VERSION 5.8 ;
BUSBITCHARS "[]" ;
DIVIDERCHAR "/" ;
UNITS
    DATABASE MICRONS 1000 ;
END UNITS

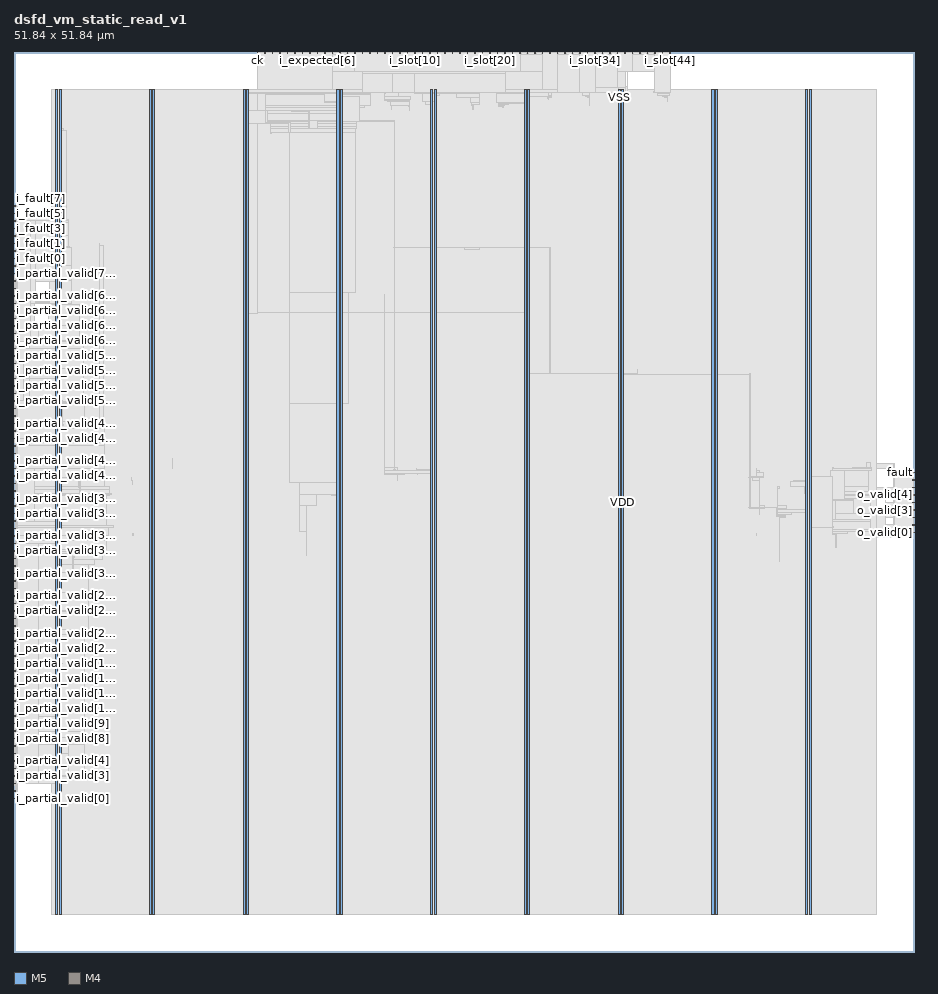
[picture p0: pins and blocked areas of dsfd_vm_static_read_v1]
MACRO dsfd_vm_static_read_v1
  FOREIGN dsfd_vm_static_read_v1 0 0 ;
  CLASS BLOCK ;
  SIZE 51.84 BY 51.84 ;
  PIN ck
    DIRECTION INPUT ;
    USE SIGNAL ;
    PORT
      LAYER M5 ;
        RECT  14.016 51.756 14.04 51.84 ;
    END
  END ck
  PIN fault
    DIRECTION OUTPUT ;
    USE SIGNAL ;
    PORT
      LAYER M4 ;
        RECT  51.756 27.6 51.84 27.624 ;
    END
  END fault
  PIN i_expected[0]
    DIRECTION INPUT ;
    USE SIGNAL ;
    PORT
      LAYER M5 ;
        RECT  14.88 51.756 14.904 51.84 ;
    END
  END i_expected[0]
  PIN i_expected[1]
    DIRECTION INPUT ;
    USE SIGNAL ;
    PORT
      LAYER M5 ;
        RECT  15.312 51.756 15.336 51.84 ;
    END
  END i_expected[1]
  PIN i_expected[2]
    DIRECTION INPUT ;
    USE SIGNAL ;
    PORT
      LAYER M5 ;
        RECT  15.744 51.756 15.768 51.84 ;
    END
  END i_expected[2]
  PIN i_expected[3]
    DIRECTION INPUT ;
    USE SIGNAL ;
    PORT
      LAYER M5 ;
        RECT  16.176 51.756 16.2 51.84 ;
    END
  END i_expected[3]
  PIN i_expected[4]
    DIRECTION INPUT ;
    USE SIGNAL ;
    PORT
      LAYER M5 ;
        RECT  16.608 51.756 16.632 51.84 ;
    END
  END i_expected[4]
  PIN i_expected[5]
    DIRECTION INPUT ;
    USE SIGNAL ;
    PORT
      LAYER M5 ;
        RECT  17.04 51.756 17.064 51.84 ;
    END
  END i_expected[5]
  PIN i_expected[6]
    DIRECTION INPUT ;
    USE SIGNAL ;
    PORT
      LAYER M5 ;
        RECT  17.472 51.756 17.496 51.84 ;
    END
  END i_expected[6]
  PIN i_expected[7]
    DIRECTION INPUT ;
    USE SIGNAL ;
    PORT
      LAYER M5 ;
        RECT  17.904 51.756 17.928 51.84 ;
    END
  END i_expected[7]
  PIN i_expected[8]
    DIRECTION INPUT ;
    USE SIGNAL ;
    PORT
      LAYER M5 ;
        RECT  18.336 51.756 18.36 51.84 ;
    END
  END i_expected[8]
  PIN i_fault[0]
    DIRECTION INPUT ;
    USE SIGNAL ;
    PORT
      LAYER M4 ;
        RECT  0 39.936 0.084 39.96 ;
    END
  END i_fault[0]
  PIN i_fault[1]
    DIRECTION INPUT ;
    USE SIGNAL ;
    PORT
      LAYER M4 ;
        RECT  0 40.368 0.084 40.392 ;
    END
  END i_fault[1]
  PIN i_fault[2]
    DIRECTION INPUT ;
    USE SIGNAL ;
    PORT
      LAYER M4 ;
        RECT  0 40.8 0.084 40.824 ;
    END
  END i_fault[2]
  PIN i_fault[3]
    DIRECTION INPUT ;
    USE SIGNAL ;
    PORT
      LAYER M4 ;
        RECT  0 41.232 0.084 41.256 ;
    END
  END i_fault[3]
  PIN i_fault[4]
    DIRECTION INPUT ;
    USE SIGNAL ;
    PORT
      LAYER M4 ;
        RECT  0 41.664 0.084 41.688 ;
    END
  END i_fault[4]
  PIN i_fault[5]
    DIRECTION INPUT ;
    USE SIGNAL ;
    PORT
      LAYER M4 ;
        RECT  0 42.096 0.084 42.12 ;
    END
  END i_fault[5]
  PIN i_fault[6]
    DIRECTION INPUT ;
    USE SIGNAL ;
    PORT
      LAYER M4 ;
        RECT  0 42.528 0.084 42.552 ;
    END
  END i_fault[6]
  PIN i_fault[7]
    DIRECTION INPUT ;
    USE SIGNAL ;
    PORT
      LAYER M4 ;
        RECT  0 42.96 0.084 42.984 ;
    END
  END i_fault[7]
  PIN i_partial_valid[0]
    DIRECTION INPUT ;
    USE SIGNAL ;
    PORT
      LAYER M4 ;
        RECT  0 8.832 0.084 8.856 ;
    END
  END i_partial_valid[0]
  PIN i_partial_valid[10]
    DIRECTION INPUT ;
    USE SIGNAL ;
    PORT
      LAYER M4 ;
        RECT  0 13.152 0.084 13.176 ;
    END
  END i_partial_valid[10]
  PIN i_partial_valid[11]
    DIRECTION INPUT ;
    USE SIGNAL ;
    PORT
      LAYER M4 ;
        RECT  0 13.584 0.084 13.608 ;
    END
  END i_partial_valid[11]
  PIN i_partial_valid[12]
    DIRECTION INPUT ;
    USE SIGNAL ;
    PORT
      LAYER M4 ;
        RECT  0 14.016 0.084 14.04 ;
    END
  END i_partial_valid[12]
  PIN i_partial_valid[13]
    DIRECTION INPUT ;
    USE SIGNAL ;
    PORT
      LAYER M4 ;
        RECT  0 14.448 0.084 14.472 ;
    END
  END i_partial_valid[13]
  PIN i_partial_valid[14]
    DIRECTION INPUT ;
    USE SIGNAL ;
    PORT
      LAYER M4 ;
        RECT  0 14.88 0.084 14.904 ;
    END
  END i_partial_valid[14]
  PIN i_partial_valid[15]
    DIRECTION INPUT ;
    USE SIGNAL ;
    PORT
      LAYER M4 ;
        RECT  0 15.312 0.084 15.336 ;
    END
  END i_partial_valid[15]
  PIN i_partial_valid[16]
    DIRECTION INPUT ;
    USE SIGNAL ;
    PORT
      LAYER M4 ;
        RECT  0 15.744 0.084 15.768 ;
    END
  END i_partial_valid[16]
  PIN i_partial_valid[17]
    DIRECTION INPUT ;
    USE SIGNAL ;
    PORT
      LAYER M4 ;
        RECT  0 16.176 0.084 16.2 ;
    END
  END i_partial_valid[17]
  PIN i_partial_valid[18]
    DIRECTION INPUT ;
    USE SIGNAL ;
    PORT
      LAYER M4 ;
        RECT  0 16.608 0.084 16.632 ;
    END
  END i_partial_valid[18]
  PIN i_partial_valid[19]
    DIRECTION INPUT ;
    USE SIGNAL ;
    PORT
      LAYER M4 ;
        RECT  0 17.04 0.084 17.064 ;
    END
  END i_partial_valid[19]
  PIN i_partial_valid[1]
    DIRECTION INPUT ;
    USE SIGNAL ;
    PORT
      LAYER M4 ;
        RECT  0 9.264 0.084 9.288 ;
    END
  END i_partial_valid[1]
  PIN i_partial_valid[20]
    DIRECTION INPUT ;
    USE SIGNAL ;
    PORT
      LAYER M4 ;
        RECT  0 17.472 0.084 17.496 ;
    END
  END i_partial_valid[20]
  PIN i_partial_valid[21]
    DIRECTION INPUT ;
    USE SIGNAL ;
    PORT
      LAYER M4 ;
        RECT  0 17.904 0.084 17.928 ;
    END
  END i_partial_valid[21]
  PIN i_partial_valid[22]
    DIRECTION INPUT ;
    USE SIGNAL ;
    PORT
      LAYER M4 ;
        RECT  0 18.336 0.084 18.36 ;
    END
  END i_partial_valid[22]
  PIN i_partial_valid[23]
    DIRECTION INPUT ;
    USE SIGNAL ;
    PORT
      LAYER M4 ;
        RECT  0 18.768 0.084 18.792 ;
    END
  END i_partial_valid[23]
  PIN i_partial_valid[24]
    DIRECTION INPUT ;
    USE SIGNAL ;
    PORT
      LAYER M4 ;
        RECT  0 19.2 0.084 19.224 ;
    END
  END i_partial_valid[24]
  PIN i_partial_valid[25]
    DIRECTION INPUT ;
    USE SIGNAL ;
    PORT
      LAYER M4 ;
        RECT  0 19.632 0.084 19.656 ;
    END
  END i_partial_valid[25]
  PIN i_partial_valid[26]
    DIRECTION INPUT ;
    USE SIGNAL ;
    PORT
      LAYER M4 ;
        RECT  0 20.064 0.084 20.088 ;
    END
  END i_partial_valid[26]
  PIN i_partial_valid[27]
    DIRECTION INPUT ;
    USE SIGNAL ;
    PORT
      LAYER M4 ;
        RECT  0 20.496 0.084 20.52 ;
    END
  END i_partial_valid[27]
  PIN i_partial_valid[28]
    DIRECTION INPUT ;
    USE SIGNAL ;
    PORT
      LAYER M4 ;
        RECT  0 20.928 0.084 20.952 ;
    END
  END i_partial_valid[28]
  PIN i_partial_valid[29]
    DIRECTION INPUT ;
    USE SIGNAL ;
    PORT
      LAYER M4 ;
        RECT  0 21.36 0.084 21.384 ;
    END
  END i_partial_valid[29]
  PIN i_partial_valid[2]
    DIRECTION INPUT ;
    USE SIGNAL ;
    PORT
      LAYER M4 ;
        RECT  0 9.696 0.084 9.72 ;
    END
  END i_partial_valid[2]
  PIN i_partial_valid[30]
    DIRECTION INPUT ;
    USE SIGNAL ;
    PORT
      LAYER M4 ;
        RECT  0 21.792 0.084 21.816 ;
    END
  END i_partial_valid[30]
  PIN i_partial_valid[31]
    DIRECTION INPUT ;
    USE SIGNAL ;
    PORT
      LAYER M4 ;
        RECT  0 22.224 0.084 22.248 ;
    END
  END i_partial_valid[31]
  PIN i_partial_valid[32]
    DIRECTION INPUT ;
    USE SIGNAL ;
    PORT
      LAYER M4 ;
        RECT  0 22.656 0.084 22.68 ;
    END
  END i_partial_valid[32]
  PIN i_partial_valid[33]
    DIRECTION INPUT ;
    USE SIGNAL ;
    PORT
      LAYER M4 ;
        RECT  0 23.088 0.084 23.112 ;
    END
  END i_partial_valid[33]
  PIN i_partial_valid[34]
    DIRECTION INPUT ;
    USE SIGNAL ;
    PORT
      LAYER M4 ;
        RECT  0 23.52 0.084 23.544 ;
    END
  END i_partial_valid[34]
  PIN i_partial_valid[35]
    DIRECTION INPUT ;
    USE SIGNAL ;
    PORT
      LAYER M4 ;
        RECT  0 23.952 0.084 23.976 ;
    END
  END i_partial_valid[35]
  PIN i_partial_valid[36]
    DIRECTION INPUT ;
    USE SIGNAL ;
    PORT
      LAYER M4 ;
        RECT  0 24.384 0.084 24.408 ;
    END
  END i_partial_valid[36]
  PIN i_partial_valid[37]
    DIRECTION INPUT ;
    USE SIGNAL ;
    PORT
      LAYER M4 ;
        RECT  0 24.816 0.084 24.84 ;
    END
  END i_partial_valid[37]
  PIN i_partial_valid[38]
    DIRECTION INPUT ;
    USE SIGNAL ;
    PORT
      LAYER M4 ;
        RECT  0 25.248 0.084 25.272 ;
    END
  END i_partial_valid[38]
  PIN i_partial_valid[39]
    DIRECTION INPUT ;
    USE SIGNAL ;
    PORT
      LAYER M4 ;
        RECT  0 25.68 0.084 25.704 ;
    END
  END i_partial_valid[39]
  PIN i_partial_valid[3]
    DIRECTION INPUT ;
    USE SIGNAL ;
    PORT
      LAYER M4 ;
        RECT  0 10.128 0.084 10.152 ;
    END
  END i_partial_valid[3]
  PIN i_partial_valid[40]
    DIRECTION INPUT ;
    USE SIGNAL ;
    PORT
      LAYER M4 ;
        RECT  0 26.112 0.084 26.136 ;
    END
  END i_partial_valid[40]
  PIN i_partial_valid[41]
    DIRECTION INPUT ;
    USE SIGNAL ;
    PORT
      LAYER M4 ;
        RECT  0 26.544 0.084 26.568 ;
    END
  END i_partial_valid[41]
  PIN i_partial_valid[42]
    DIRECTION INPUT ;
    USE SIGNAL ;
    PORT
      LAYER M4 ;
        RECT  0 26.976 0.084 27 ;
    END
  END i_partial_valid[42]
  PIN i_partial_valid[43]
    DIRECTION INPUT ;
    USE SIGNAL ;
    PORT
      LAYER M4 ;
        RECT  0 27.408 0.084 27.432 ;
    END
  END i_partial_valid[43]
  PIN i_partial_valid[44]
    DIRECTION INPUT ;
    USE SIGNAL ;
    PORT
      LAYER M4 ;
        RECT  0 27.84 0.084 27.864 ;
    END
  END i_partial_valid[44]
  PIN i_partial_valid[45]
    DIRECTION INPUT ;
    USE SIGNAL ;
    PORT
      LAYER M4 ;
        RECT  0 28.272 0.084 28.296 ;
    END
  END i_partial_valid[45]
  PIN i_partial_valid[46]
    DIRECTION INPUT ;
    USE SIGNAL ;
    PORT
      LAYER M4 ;
        RECT  0 28.704 0.084 28.728 ;
    END
  END i_partial_valid[46]
  PIN i_partial_valid[47]
    DIRECTION INPUT ;
    USE SIGNAL ;
    PORT
      LAYER M4 ;
        RECT  0 29.136 0.084 29.16 ;
    END
  END i_partial_valid[47]
  PIN i_partial_valid[48]
    DIRECTION INPUT ;
    USE SIGNAL ;
    PORT
      LAYER M4 ;
        RECT  0 29.568 0.084 29.592 ;
    END
  END i_partial_valid[48]
  PIN i_partial_valid[49]
    DIRECTION INPUT ;
    USE SIGNAL ;
    PORT
      LAYER M4 ;
        RECT  0 30 0.084 30.024 ;
    END
  END i_partial_valid[49]
  PIN i_partial_valid[4]
    DIRECTION INPUT ;
    USE SIGNAL ;
    PORT
      LAYER M4 ;
        RECT  0 10.56 0.084 10.584 ;
    END
  END i_partial_valid[4]
  PIN i_partial_valid[50]
    DIRECTION INPUT ;
    USE SIGNAL ;
    PORT
      LAYER M4 ;
        RECT  0 30.432 0.084 30.456 ;
    END
  END i_partial_valid[50]
  PIN i_partial_valid[51]
    DIRECTION INPUT ;
    USE SIGNAL ;
    PORT
      LAYER M4 ;
        RECT  0 30.864 0.084 30.888 ;
    END
  END i_partial_valid[51]
  PIN i_partial_valid[52]
    DIRECTION INPUT ;
    USE SIGNAL ;
    PORT
      LAYER M4 ;
        RECT  0 31.296 0.084 31.32 ;
    END
  END i_partial_valid[52]
  PIN i_partial_valid[53]
    DIRECTION INPUT ;
    USE SIGNAL ;
    PORT
      LAYER M4 ;
        RECT  0 31.728 0.084 31.752 ;
    END
  END i_partial_valid[53]
  PIN i_partial_valid[54]
    DIRECTION INPUT ;
    USE SIGNAL ;
    PORT
      LAYER M4 ;
        RECT  0 32.16 0.084 32.184 ;
    END
  END i_partial_valid[54]
  PIN i_partial_valid[55]
    DIRECTION INPUT ;
    USE SIGNAL ;
    PORT
      LAYER M4 ;
        RECT  0 32.592 0.084 32.616 ;
    END
  END i_partial_valid[55]
  PIN i_partial_valid[56]
    DIRECTION INPUT ;
    USE SIGNAL ;
    PORT
      LAYER M4 ;
        RECT  0 33.024 0.084 33.048 ;
    END
  END i_partial_valid[56]
  PIN i_partial_valid[57]
    DIRECTION INPUT ;
    USE SIGNAL ;
    PORT
      LAYER M4 ;
        RECT  0 33.456 0.084 33.48 ;
    END
  END i_partial_valid[57]
  PIN i_partial_valid[58]
    DIRECTION INPUT ;
    USE SIGNAL ;
    PORT
      LAYER M4 ;
        RECT  0 33.888 0.084 33.912 ;
    END
  END i_partial_valid[58]
  PIN i_partial_valid[59]
    DIRECTION INPUT ;
    USE SIGNAL ;
    PORT
      LAYER M4 ;
        RECT  0 34.32 0.084 34.344 ;
    END
  END i_partial_valid[59]
  PIN i_partial_valid[5]
    DIRECTION INPUT ;
    USE SIGNAL ;
    PORT
      LAYER M4 ;
        RECT  0 10.992 0.084 11.016 ;
    END
  END i_partial_valid[5]
  PIN i_partial_valid[60]
    DIRECTION INPUT ;
    USE SIGNAL ;
    PORT
      LAYER M4 ;
        RECT  0 34.752 0.084 34.776 ;
    END
  END i_partial_valid[60]
  PIN i_partial_valid[61]
    DIRECTION INPUT ;
    USE SIGNAL ;
    PORT
      LAYER M4 ;
        RECT  0 35.184 0.084 35.208 ;
    END
  END i_partial_valid[61]
  PIN i_partial_valid[62]
    DIRECTION INPUT ;
    USE SIGNAL ;
    PORT
      LAYER M4 ;
        RECT  0 35.616 0.084 35.64 ;
    END
  END i_partial_valid[62]
  PIN i_partial_valid[63]
    DIRECTION INPUT ;
    USE SIGNAL ;
    PORT
      LAYER M4 ;
        RECT  0 36.048 0.084 36.072 ;
    END
  END i_partial_valid[63]
  PIN i_partial_valid[64]
    DIRECTION INPUT ;
    USE SIGNAL ;
    PORT
      LAYER M4 ;
        RECT  0 36.48 0.084 36.504 ;
    END
  END i_partial_valid[64]
  PIN i_partial_valid[65]
    DIRECTION INPUT ;
    USE SIGNAL ;
    PORT
      LAYER M4 ;
        RECT  0 36.912 0.084 36.936 ;
    END
  END i_partial_valid[65]
  PIN i_partial_valid[66]
    DIRECTION INPUT ;
    USE SIGNAL ;
    PORT
      LAYER M4 ;
        RECT  0 37.344 0.084 37.368 ;
    END
  END i_partial_valid[66]
  PIN i_partial_valid[67]
    DIRECTION INPUT ;
    USE SIGNAL ;
    PORT
      LAYER M4 ;
        RECT  0 37.776 0.084 37.8 ;
    END
  END i_partial_valid[67]
  PIN i_partial_valid[68]
    DIRECTION INPUT ;
    USE SIGNAL ;
    PORT
      LAYER M4 ;
        RECT  0 38.208 0.084 38.232 ;
    END
  END i_partial_valid[68]
  PIN i_partial_valid[69]
    DIRECTION INPUT ;
    USE SIGNAL ;
    PORT
      LAYER M4 ;
        RECT  0 38.64 0.084 38.664 ;
    END
  END i_partial_valid[69]
  PIN i_partial_valid[6]
    DIRECTION INPUT ;
    USE SIGNAL ;
    PORT
      LAYER M4 ;
        RECT  0 11.424 0.084 11.448 ;
    END
  END i_partial_valid[6]
  PIN i_partial_valid[70]
    DIRECTION INPUT ;
    USE SIGNAL ;
    PORT
      LAYER M4 ;
        RECT  0 39.072 0.084 39.096 ;
    END
  END i_partial_valid[70]
  PIN i_partial_valid[71]
    DIRECTION INPUT ;
    USE SIGNAL ;
    PORT
      LAYER M4 ;
        RECT  0 39.504 0.084 39.528 ;
    END
  END i_partial_valid[71]
  PIN i_partial_valid[7]
    DIRECTION INPUT ;
    USE SIGNAL ;
    PORT
      LAYER M4 ;
        RECT  0 11.856 0.084 11.88 ;
    END
  END i_partial_valid[7]
  PIN i_partial_valid[8]
    DIRECTION INPUT ;
    USE SIGNAL ;
    PORT
      LAYER M4 ;
        RECT  0 12.288 0.084 12.312 ;
    END
  END i_partial_valid[8]
  PIN i_partial_valid[9]
    DIRECTION INPUT ;
    USE SIGNAL ;
    PORT
      LAYER M4 ;
        RECT  0 12.72 0.084 12.744 ;
    END
  END i_partial_valid[9]
  PIN i_slot[0]
    DIRECTION INPUT ;
    USE SIGNAL ;
    PORT
      LAYER M5 ;
        RECT  18.768 51.756 18.792 51.84 ;
    END
  END i_slot[0]
  PIN i_slot[10]
    DIRECTION INPUT ;
    USE SIGNAL ;
    PORT
      LAYER M5 ;
        RECT  23.088 51.756 23.112 51.84 ;
    END
  END i_slot[10]
  PIN i_slot[11]
    DIRECTION INPUT ;
    USE SIGNAL ;
    PORT
      LAYER M5 ;
        RECT  23.52 51.756 23.544 51.84 ;
    END
  END i_slot[11]
  PIN i_slot[12]
    DIRECTION INPUT ;
    USE SIGNAL ;
    PORT
      LAYER M5 ;
        RECT  23.952 51.756 23.976 51.84 ;
    END
  END i_slot[12]
  PIN i_slot[13]
    DIRECTION INPUT ;
    USE SIGNAL ;
    PORT
      LAYER M5 ;
        RECT  24.384 51.756 24.408 51.84 ;
    END
  END i_slot[13]
  PIN i_slot[14]
    DIRECTION INPUT ;
    USE SIGNAL ;
    PORT
      LAYER M5 ;
        RECT  24.816 51.756 24.84 51.84 ;
    END
  END i_slot[14]
  PIN i_slot[15]
    DIRECTION INPUT ;
    USE SIGNAL ;
    PORT
      LAYER M5 ;
        RECT  25.248 51.756 25.272 51.84 ;
    END
  END i_slot[15]
  PIN i_slot[16]
    DIRECTION INPUT ;
    USE SIGNAL ;
    PORT
      LAYER M5 ;
        RECT  25.68 51.756 25.704 51.84 ;
    END
  END i_slot[16]
  PIN i_slot[17]
    DIRECTION INPUT ;
    USE SIGNAL ;
    PORT
      LAYER M5 ;
        RECT  26.112 51.756 26.136 51.84 ;
    END
  END i_slot[17]
  PIN i_slot[18]
    DIRECTION INPUT ;
    USE SIGNAL ;
    PORT
      LAYER M5 ;
        RECT  26.544 51.756 26.568 51.84 ;
    END
  END i_slot[18]
  PIN i_slot[19]
    DIRECTION INPUT ;
    USE SIGNAL ;
    PORT
      LAYER M5 ;
        RECT  26.976 51.756 27 51.84 ;
    END
  END i_slot[19]
  PIN i_slot[1]
    DIRECTION INPUT ;
    USE SIGNAL ;
    PORT
      LAYER M5 ;
        RECT  19.2 51.756 19.224 51.84 ;
    END
  END i_slot[1]
  PIN i_slot[20]
    DIRECTION INPUT ;
    USE SIGNAL ;
    PORT
      LAYER M5 ;
        RECT  27.408 51.756 27.432 51.84 ;
    END
  END i_slot[20]
  PIN i_slot[21]
    DIRECTION INPUT ;
    USE SIGNAL ;
    PORT
      LAYER M5 ;
        RECT  27.84 51.756 27.864 51.84 ;
    END
  END i_slot[21]
  PIN i_slot[22]
    DIRECTION INPUT ;
    USE SIGNAL ;
    PORT
      LAYER M5 ;
        RECT  28.272 51.756 28.296 51.84 ;
    END
  END i_slot[22]
  PIN i_slot[23]
    DIRECTION INPUT ;
    USE SIGNAL ;
    PORT
      LAYER M5 ;
        RECT  28.704 51.756 28.728 51.84 ;
    END
  END i_slot[23]
  PIN i_slot[24]
    DIRECTION INPUT ;
    USE SIGNAL ;
    PORT
      LAYER M5 ;
        RECT  29.136 51.756 29.16 51.84 ;
    END
  END i_slot[24]
  PIN i_slot[25]
    DIRECTION INPUT ;
    USE SIGNAL ;
    PORT
      LAYER M5 ;
        RECT  29.568 51.756 29.592 51.84 ;
    END
  END i_slot[25]
  PIN i_slot[26]
    DIRECTION INPUT ;
    USE SIGNAL ;
    PORT
      LAYER M5 ;
        RECT  30 51.756 30.024 51.84 ;
    END
  END i_slot[26]
  PIN i_slot[27]
    DIRECTION INPUT ;
    USE SIGNAL ;
    PORT
      LAYER M5 ;
        RECT  30.432 51.756 30.456 51.84 ;
    END
  END i_slot[27]
  PIN i_slot[28]
    DIRECTION INPUT ;
    USE SIGNAL ;
    PORT
      LAYER M5 ;
        RECT  30.864 51.756 30.888 51.84 ;
    END
  END i_slot[28]
  PIN i_slot[29]
    DIRECTION INPUT ;
    USE SIGNAL ;
    PORT
      LAYER M5 ;
        RECT  31.296 51.756 31.32 51.84 ;
    END
  END i_slot[29]
  PIN i_slot[2]
    DIRECTION INPUT ;
    USE SIGNAL ;
    PORT
      LAYER M5 ;
        RECT  19.632 51.756 19.656 51.84 ;
    END
  END i_slot[2]
  PIN i_slot[30]
    DIRECTION INPUT ;
    USE SIGNAL ;
    PORT
      LAYER M5 ;
        RECT  31.728 51.756 31.752 51.84 ;
    END
  END i_slot[30]
  PIN i_slot[31]
    DIRECTION INPUT ;
    USE SIGNAL ;
    PORT
      LAYER M5 ;
        RECT  32.16 51.756 32.184 51.84 ;
    END
  END i_slot[31]
  PIN i_slot[32]
    DIRECTION INPUT ;
    USE SIGNAL ;
    PORT
      LAYER M5 ;
        RECT  32.592 51.756 32.616 51.84 ;
    END
  END i_slot[32]
  PIN i_slot[33]
    DIRECTION INPUT ;
    USE SIGNAL ;
    PORT
      LAYER M5 ;
        RECT  33.024 51.756 33.048 51.84 ;
    END
  END i_slot[33]
  PIN i_slot[34]
    DIRECTION INPUT ;
    USE SIGNAL ;
    PORT
      LAYER M5 ;
        RECT  33.456 51.756 33.48 51.84 ;
    END
  END i_slot[34]
  PIN i_slot[35]
    DIRECTION INPUT ;
    USE SIGNAL ;
    PORT
      LAYER M5 ;
        RECT  33.888 51.756 33.912 51.84 ;
    END
  END i_slot[35]
  PIN i_slot[36]
    DIRECTION INPUT ;
    USE SIGNAL ;
    PORT
      LAYER M5 ;
        RECT  34.32 51.756 34.344 51.84 ;
    END
  END i_slot[36]
  PIN i_slot[37]
    DIRECTION INPUT ;
    USE SIGNAL ;
    PORT
      LAYER M5 ;
        RECT  34.752 51.756 34.776 51.84 ;
    END
  END i_slot[37]
  PIN i_slot[38]
    DIRECTION INPUT ;
    USE SIGNAL ;
    PORT
      LAYER M5 ;
        RECT  35.184 51.756 35.208 51.84 ;
    END
  END i_slot[38]
  PIN i_slot[39]
    DIRECTION INPUT ;
    USE SIGNAL ;
    PORT
      LAYER M5 ;
        RECT  35.616 51.756 35.64 51.84 ;
    END
  END i_slot[39]
  PIN i_slot[3]
    DIRECTION INPUT ;
    USE SIGNAL ;
    PORT
      LAYER M5 ;
        RECT  20.064 51.756 20.088 51.84 ;
    END
  END i_slot[3]
  PIN i_slot[40]
    DIRECTION INPUT ;
    USE SIGNAL ;
    PORT
      LAYER M5 ;
        RECT  36.048 51.756 36.072 51.84 ;
    END
  END i_slot[40]
  PIN i_slot[41]
    DIRECTION INPUT ;
    USE SIGNAL ;
    PORT
      LAYER M5 ;
        RECT  36.48 51.756 36.504 51.84 ;
    END
  END i_slot[41]
  PIN i_slot[42]
    DIRECTION INPUT ;
    USE SIGNAL ;
    PORT
      LAYER M5 ;
        RECT  36.912 51.756 36.936 51.84 ;
    END
  END i_slot[42]
  PIN i_slot[43]
    DIRECTION INPUT ;
    USE SIGNAL ;
    PORT
      LAYER M5 ;
        RECT  37.344 51.756 37.368 51.84 ;
    END
  END i_slot[43]
  PIN i_slot[44]
    DIRECTION INPUT ;
    USE SIGNAL ;
    PORT
      LAYER M5 ;
        RECT  37.776 51.756 37.8 51.84 ;
    END
  END i_slot[44]
  PIN i_slot[4]
    DIRECTION INPUT ;
    USE SIGNAL ;
    PORT
      LAYER M5 ;
        RECT  20.496 51.756 20.52 51.84 ;
    END
  END i_slot[4]
  PIN i_slot[5]
    DIRECTION INPUT ;
    USE SIGNAL ;
    PORT
      LAYER M5 ;
        RECT  20.928 51.756 20.952 51.84 ;
    END
  END i_slot[5]
  PIN i_slot[6]
    DIRECTION INPUT ;
    USE SIGNAL ;
    PORT
      LAYER M5 ;
        RECT  21.36 51.756 21.384 51.84 ;
    END
  END i_slot[6]
  PIN i_slot[7]
    DIRECTION INPUT ;
    USE SIGNAL ;
    PORT
      LAYER M5 ;
        RECT  21.792 51.756 21.816 51.84 ;
    END
  END i_slot[7]
  PIN i_slot[8]
    DIRECTION INPUT ;
    USE SIGNAL ;
    PORT
      LAYER M5 ;
        RECT  22.224 51.756 22.248 51.84 ;
    END
  END i_slot[8]
  PIN i_slot[9]
    DIRECTION INPUT ;
    USE SIGNAL ;
    PORT
      LAYER M5 ;
        RECT  22.656 51.756 22.68 51.84 ;
    END
  END i_slot[9]
  PIN o_valid[0]
    DIRECTION OUTPUT ;
    USE SIGNAL ;
    PORT
      LAYER M4 ;
        RECT  51.756 24.144 51.84 24.168 ;
    END
  END o_valid[0]
  PIN o_valid[1]
    DIRECTION OUTPUT ;
    USE SIGNAL ;
    PORT
      LAYER M4 ;
        RECT  51.756 24.576 51.84 24.6 ;
    END
  END o_valid[1]
  PIN o_valid[2]
    DIRECTION OUTPUT ;
    USE SIGNAL ;
    PORT
      LAYER M4 ;
        RECT  51.756 25.008 51.84 25.032 ;
    END
  END o_valid[2]
  PIN o_valid[3]
    DIRECTION OUTPUT ;
    USE SIGNAL ;
    PORT
      LAYER M4 ;
        RECT  51.756 25.44 51.84 25.464 ;
    END
  END o_valid[3]
  PIN o_valid[4]
    DIRECTION OUTPUT ;
    USE SIGNAL ;
    PORT
      LAYER M4 ;
        RECT  51.756 25.872 51.84 25.896 ;
    END
  END o_valid[4]
  PIN o_valid[5]
    DIRECTION OUTPUT ;
    USE SIGNAL ;
    PORT
      LAYER M4 ;
        RECT  51.756 26.304 51.84 26.328 ;
    END
  END o_valid[5]
  PIN o_valid[6]
    DIRECTION OUTPUT ;
    USE SIGNAL ;
    PORT
      LAYER M4 ;
        RECT  51.756 26.736 51.84 26.76 ;
    END
  END o_valid[6]
  PIN o_valid[7]
    DIRECTION OUTPUT ;
    USE SIGNAL ;
    PORT
      LAYER M4 ;
        RECT  51.756 27.168 51.84 27.192 ;
    END
  END o_valid[7]
  PIN rst_n
    DIRECTION INPUT ;
    USE SIGNAL ;
    PORT
      LAYER M5 ;
        RECT  14.448 51.756 14.472 51.84 ;
    END
  END rst_n
  PIN VDD
    DIRECTION INOUT ;
    USE POWER ;
    PORT
      LAYER M5 ;
        RECT  45.792 2.151 45.912 49.689 ;
        RECT  40.392 2.151 40.512 49.689 ;
        RECT  34.992 2.151 35.112 49.689 ;
        RECT  29.592 2.151 29.712 49.689 ;
        RECT  24.192 2.151 24.312 49.689 ;
        RECT  18.792 2.151 18.912 49.689 ;
        RECT  13.392 2.151 13.512 49.689 ;
        RECT  7.992 2.151 8.112 49.689 ;
        RECT  2.592 2.151 2.712 49.689 ;
    END
  END VDD
  PIN VSS
    DIRECTION INOUT ;
    USE GROUND ;
    PORT
      LAYER M5 ;
        RECT  45.6 2.137 45.72 49.703 ;
        RECT  40.2 2.137 40.32 49.703 ;
        RECT  34.8 2.137 34.92 49.703 ;
        RECT  29.4 2.137 29.52 49.703 ;
        RECT  24 2.137 24.12 49.703 ;
        RECT  18.6 2.137 18.72 49.703 ;
        RECT  13.2 2.137 13.32 49.703 ;
        RECT  7.8 2.137 7.92 49.703 ;
        RECT  2.4 2.137 2.52 49.703 ;
    END
  END VSS
  # OT_OBS_CLOSED layer=M5 d_um=1.536 added=31
  OBS
    LAYER RVTN ;
     RECT  2.16 2.16 49.68 2.295 ;
     RECT  2.16 2.565 49.68 2.835 ;
     RECT  2.16 3.105 49.68 3.375 ;
     RECT  2.16 3.645 49.68 3.915 ;
     RECT  2.16 4.185 49.68 4.455 ;
     RECT  2.16 4.725 49.68 4.995 ;
     RECT  2.16 5.265 49.68 5.535 ;
     RECT  2.16 5.805 49.68 6.075 ;
     RECT  2.16 6.345 49.68 6.615 ;
     RECT  2.16 6.885 49.68 7.155 ;
     RECT  2.16 7.425 49.68 7.695 ;
     RECT  2.16 7.965 49.68 8.235 ;
     RECT  2.16 8.505 49.68 8.775 ;
     RECT  2.16 9.045 49.68 9.315 ;
     RECT  2.16 9.585 49.68 9.855 ;
     RECT  2.16 10.125 49.68 10.395 ;
     RECT  2.16 10.665 49.68 10.935 ;
     RECT  2.16 11.205 49.68 11.475 ;
     RECT  2.16 11.745 49.68 12.015 ;
     RECT  2.16 12.285 49.68 12.555 ;
     RECT  2.16 12.825 49.68 13.095 ;
     RECT  2.16 13.365 49.68 13.635 ;
     RECT  2.16 13.905 49.68 14.175 ;
     RECT  2.16 14.445 49.68 14.715 ;
     RECT  2.16 14.985 49.68 15.255 ;
     RECT  2.16 15.525 49.68 15.795 ;
     RECT  2.16 16.065 49.68 16.335 ;
     RECT  2.16 16.605 49.68 16.875 ;
     RECT  2.16 17.145 49.68 17.415 ;
     RECT  2.16 17.685 49.68 17.955 ;
     RECT  2.16 18.225 49.68 18.495 ;
     RECT  2.16 18.765 49.68 19.035 ;
     RECT  2.16 19.305 49.68 19.575 ;
     RECT  2.16 19.845 49.68 20.115 ;
     RECT  2.16 20.385 49.68 20.655 ;
     RECT  2.16 20.925 49.68 21.195 ;
     RECT  2.16 21.465 49.68 21.735 ;
     RECT  2.16 22.005 49.68 22.275 ;
     RECT  2.16 22.545 49.68 22.815 ;
     RECT  2.16 23.085 49.68 23.355 ;
     RECT  2.16 23.625 49.68 23.895 ;
     RECT  2.16 24.165 49.68 24.435 ;
     RECT  2.16 24.705 49.68 24.975 ;
     RECT  2.16 25.245 49.68 25.515 ;
     RECT  2.16 25.785 49.68 26.055 ;
     RECT  2.16 26.325 49.68 26.595 ;
     RECT  2.16 26.865 49.68 27.135 ;
     RECT  2.16 27.405 49.68 27.675 ;
     RECT  2.16 27.945 49.68 28.215 ;
     RECT  2.16 28.485 49.68 28.755 ;
     RECT  2.16 29.025 49.68 29.295 ;
     RECT  2.16 29.565 49.68 29.835 ;
     RECT  2.16 30.105 49.68 30.375 ;
     RECT  2.16 30.645 49.68 30.915 ;
     RECT  2.16 31.185 49.68 31.455 ;
     RECT  2.16 31.725 49.68 31.995 ;
     RECT  2.16 32.265 49.68 32.535 ;
     RECT  2.16 32.805 49.68 33.075 ;
     RECT  2.16 33.345 49.68 33.615 ;
     RECT  2.16 33.885 49.68 34.155 ;
     RECT  2.16 34.425 49.68 34.695 ;
     RECT  2.16 34.965 49.68 35.235 ;
     RECT  2.16 35.505 49.68 35.775 ;
     RECT  2.16 36.045 49.68 36.315 ;
     RECT  2.16 36.585 49.68 36.855 ;
     RECT  2.16 37.125 49.68 37.395 ;
     RECT  2.16 37.665 49.68 37.935 ;
     RECT  2.16 38.205 49.68 38.475 ;
     RECT  2.16 38.745 49.68 39.015 ;
     RECT  2.16 39.285 49.68 39.555 ;
     RECT  2.16 39.825 49.68 40.095 ;
     RECT  2.16 40.365 49.68 40.635 ;
     RECT  2.16 40.905 49.68 41.175 ;
     RECT  2.16 41.445 49.68 41.715 ;
     RECT  2.16 41.985 49.68 42.255 ;
     RECT  2.16 42.525 49.68 42.795 ;
     RECT  2.16 43.065 49.68 43.335 ;
     RECT  2.16 43.605 49.68 43.875 ;
     RECT  2.16 44.145 49.68 44.415 ;
     RECT  2.16 44.685 49.68 44.955 ;
     RECT  2.16 45.225 49.68 45.495 ;
     RECT  2.16 45.765 49.68 46.035 ;
     RECT  2.16 46.305 49.68 46.575 ;
     RECT  2.16 46.845 49.68 47.115 ;
     RECT  2.16 47.385 49.68 47.655 ;
     RECT  2.16 47.925 49.68 48.195 ;
     RECT  2.16 48.465 49.68 48.735 ;
     RECT  2.16 49.005 49.68 49.275 ;
     RECT  2.16 49.545 49.68 49.68 ;
    LAYER RVTP ;
     RECT  2.16 2.295 49.68 2.565 ;
     RECT  2.16 2.835 49.68 3.105 ;
     RECT  2.16 3.375 49.68 3.645 ;
     RECT  2.16 3.915 49.68 4.185 ;
     RECT  2.16 4.455 49.68 4.725 ;
     RECT  2.16 4.995 49.68 5.265 ;
     RECT  2.16 5.535 49.68 5.805 ;
     RECT  2.16 6.075 49.68 6.345 ;
     RECT  2.16 6.615 49.68 6.885 ;
     RECT  2.16 7.155 49.68 7.425 ;
     RECT  2.16 7.695 49.68 7.965 ;
     RECT  2.16 8.235 49.68 8.505 ;
     RECT  2.16 8.775 49.68 9.045 ;
     RECT  2.16 9.315 49.68 9.585 ;
     RECT  2.16 9.855 49.68 10.125 ;
     RECT  2.16 10.395 49.68 10.665 ;
     RECT  2.16 10.935 49.68 11.205 ;
     RECT  2.16 11.475 49.68 11.745 ;
     RECT  2.16 12.015 49.68 12.285 ;
     RECT  2.16 12.555 49.68 12.825 ;
     RECT  2.16 13.095 49.68 13.365 ;
     RECT  2.16 13.635 49.68 13.905 ;
     RECT  2.16 14.175 49.68 14.445 ;
     RECT  2.16 14.715 49.68 14.985 ;
     RECT  2.16 15.255 49.68 15.525 ;
     RECT  2.16 15.795 49.68 16.065 ;
     RECT  2.16 16.335 49.68 16.605 ;
     RECT  2.16 16.875 49.68 17.145 ;
     RECT  2.16 17.415 49.68 17.685 ;
     RECT  2.16 17.955 49.68 18.225 ;
     RECT  2.16 18.495 49.68 18.765 ;
     RECT  2.16 19.035 49.68 19.305 ;
     RECT  2.16 19.575 49.68 19.845 ;
     RECT  2.16 20.115 49.68 20.385 ;
     RECT  2.16 20.655 49.68 20.925 ;
     RECT  2.16 21.195 49.68 21.465 ;
     RECT  2.16 21.735 49.68 22.005 ;
     RECT  2.16 22.275 49.68 22.545 ;
     RECT  2.16 22.815 49.68 23.085 ;
     RECT  2.16 23.355 49.68 23.625 ;
     RECT  2.16 23.895 49.68 24.165 ;
     RECT  2.16 24.435 49.68 24.705 ;
     RECT  2.16 24.975 49.68 25.245 ;
     RECT  2.16 25.515 49.68 25.785 ;
     RECT  2.16 26.055 49.68 26.325 ;
     RECT  2.16 26.595 49.68 26.865 ;
     RECT  2.16 27.135 49.68 27.405 ;
     RECT  2.16 27.675 49.68 27.945 ;
     RECT  2.16 28.215 49.68 28.485 ;
     RECT  2.16 28.755 49.68 29.025 ;
     RECT  2.16 29.295 49.68 29.565 ;
     RECT  2.16 29.835 49.68 30.105 ;
     RECT  2.16 30.375 49.68 30.645 ;
     RECT  2.16 30.915 49.68 31.185 ;
     RECT  2.16 31.455 49.68 31.725 ;
     RECT  2.16 31.995 49.68 32.265 ;
     RECT  2.16 32.535 49.68 32.805 ;
     RECT  2.16 33.075 49.68 33.345 ;
     RECT  2.16 33.615 49.68 33.885 ;
     RECT  2.16 34.155 49.68 34.425 ;
     RECT  2.16 34.695 49.68 34.965 ;
     RECT  2.16 35.235 49.68 35.505 ;
     RECT  2.16 35.775 49.68 36.045 ;
     RECT  2.16 36.315 49.68 36.585 ;
     RECT  2.16 36.855 49.68 37.125 ;
     RECT  2.16 37.395 49.68 37.665 ;
     RECT  2.16 37.935 49.68 38.205 ;
     RECT  2.16 38.475 49.68 38.745 ;
     RECT  2.16 39.015 49.68 39.285 ;
     RECT  2.16 39.555 49.68 39.825 ;
     RECT  2.16 40.095 49.68 40.365 ;
     RECT  2.16 40.635 49.68 40.905 ;
     RECT  2.16 41.175 49.68 41.445 ;
     RECT  2.16 41.715 49.68 41.985 ;
     RECT  2.16 42.255 49.68 42.525 ;
     RECT  2.16 42.795 49.68 43.065 ;
     RECT  2.16 43.335 49.68 43.605 ;
     RECT  2.16 43.875 49.68 44.145 ;
     RECT  2.16 44.415 49.68 44.685 ;
     RECT  2.16 44.955 49.68 45.225 ;
     RECT  2.16 45.495 49.68 45.765 ;
     RECT  2.16 46.035 49.68 46.305 ;
     RECT  2.16 46.575 49.68 46.845 ;
     RECT  2.16 47.115 49.68 47.385 ;
     RECT  2.16 47.655 49.68 47.925 ;
     RECT  2.16 48.195 49.68 48.465 ;
     RECT  2.16 48.735 49.68 49.005 ;
     RECT  2.16 49.275 49.68 49.545 ;
    LAYER M1 ;
     RECT  2.16 2.151 49.68 49.689 ;
    LAYER M2 ;
     RECT  0.031 23.058 0.103 23.076 ;
     RECT  0.031 29.376 0.103 29.394 ;
     RECT  0.067 26.802 0.139 26.82 ;
     RECT  0.103 29.376 0.139 29.79 ;
     RECT  0.103 34.164 0.139 34.182 ;
     RECT  0.103 41.148 0.139 41.778 ;
     RECT  0.103 23.058 0.203 23.85 ;
     RECT  0.103 31.77 0.535 33.03 ;
     RECT  0.139 34.128 0.535 34.182 ;
     RECT  0.139 26.532 0.859 26.82 ;
     RECT  0.103 30.654 1.147 30.672 ;
     RECT  0.103 19.242 1.399 19.26 ;
     RECT  0.103 21.51 1.399 21.528 ;
     RECT  0.859 26.1 1.435 26.82 ;
     RECT  1.399 21.24 1.471 21.528 ;
     RECT  0.859 24.678 1.975 24.696 ;
     RECT  1.435 25.722 1.975 26.82 ;
     RECT  0.139 27.882 1.975 29.79 ;
     RECT  1.147 30.582 1.975 30.672 ;
     RECT  1.471 21.24 2.011 21.798 ;
     RECT  0.535 31.77 2.011 34.182 ;
     RECT  1.975 24.678 2.047 26.82 ;
     RECT  1.975 27.882 2.047 30.672 ;
     RECT  0.139 10.566 2.16 10.584 ;
     RECT  1.399 18.972 2.16 19.26 ;
     RECT  2.011 21.24 2.16 21.834 ;
     RECT  0.203 23.058 2.16 23.076 ;
     RECT  0.203 23.832 2.16 23.85 ;
     RECT  2.047 24.678 2.16 30.672 ;
     RECT  2.011 31.5 2.16 34.182 ;
     RECT  1.183 35.28 2.16 35.298 ;
     RECT  0.535 37.44 2.16 37.458 ;
     RECT  0.139 41.148 2.16 42.318 ;
     RECT  2.16 2.151 49.68 49.689 ;
     RECT  49.68 23.904 50.207 25.47 ;
     RECT  49.68 27.846 50.675 28.134 ;
     RECT  50.207 23.904 50.711 24.624 ;
     RECT  50.207 25.452 50.711 25.47 ;
     RECT  49.68 26.298 50.711 26.784 ;
     RECT  50.675 28.116 50.711 28.134 ;
     RECT  50.711 23.904 50.747 23.922 ;
    LAYER M3 ;
     RECT  2.415 2.143 2.505 2.413 ;
     RECT  7.815 2.143 7.905 2.413 ;
     RECT  13.215 2.143 13.305 2.413 ;
     RECT  18.615 2.143 18.705 2.413 ;
     RECT  24.015 2.143 24.105 2.413 ;
     RECT  29.415 2.143 29.505 2.413 ;
     RECT  34.815 2.143 34.905 2.413 ;
     RECT  40.215 2.143 40.305 2.413 ;
     RECT  45.615 2.143 45.705 2.413 ;
     RECT  0.108 8.827 0.126 9.259 ;
     RECT  0.108 9.259 0.162 9.595 ;
     RECT  0.036 9.595 0.162 9.629 ;
     RECT  2.415 2.413 2.697 9.691 ;
     RECT  2.016 9.691 2.697 10.123 ;
     RECT  0.036 9.629 0.126 10.552 ;
     RECT  0.036 10.552 0.162 10.589 ;
     RECT  2.016 10.123 3.114 11.419 ;
     RECT  0.036 10.589 0.126 11.851 ;
     RECT  4.032 10.561 4.05 11.947 ;
     RECT  0.036 11.851 0.162 12.283 ;
     RECT  1.98 11.419 3.114 12.361 ;
     RECT  3.924 11.947 4.05 12.361 ;
     RECT  0.036 12.283 0.846 12.715 ;
     RECT  1.98 12.361 4.05 12.715 ;
     RECT  0.036 12.715 4.05 18.283 ;
     RECT  0.036 18.283 4.086 18.571 ;
     RECT  0.036 18.571 4.302 22.315 ;
     RECT  0.036 22.315 4.662 22.621 ;
     RECT  0.036 22.621 5.094 22.981 ;
     RECT  0.036 22.981 5.166 23.081 ;
     RECT  0.072 23.081 5.166 23.161 ;
     RECT  0.072 23.161 5.31 23.701 ;
     RECT  0.072 23.701 5.382 23.971 ;
     RECT  47.34 23.323 47.358 24.061 ;
     RECT  49.356 23.935 49.374 24.061 ;
     RECT  42.768 23.971 42.786 24.089 ;
     RECT  47.124 24.061 47.358 24.097 ;
     RECT  6.84 23.971 6.858 24.125 ;
     RECT  50.724 23.899 50.742 24.173 ;
     RECT  16.848 22.855 16.866 24.205 ;
     RECT  47.124 24.097 48.006 24.241 ;
     RECT  49.32 24.061 49.374 24.241 ;
     RECT  47.124 24.241 49.374 24.359 ;
     RECT  0.072 23.971 5.454 24.439 ;
     RECT  0.072 24.439 5.706 24.539 ;
     RECT  50.688 24.571 50.706 24.629 ;
     RECT  45.615 2.413 45.897 24.637 ;
     RECT  45.615 24.637 46.386 24.709 ;
     RECT  45.576 24.709 46.386 24.781 ;
     RECT  47.124 24.359 49.338 24.781 ;
     RECT  45.576 24.781 49.338 24.935 ;
     RECT  50.184 24.781 50.202 25.037 ;
     RECT  44.1 22.513 44.118 25.051 ;
     RECT  44.1 25.051 44.442 25.099 ;
     RECT  43.956 25.099 44.442 25.177 ;
     RECT  47.34 24.935 49.338 25.241 ;
     RECT  43.956 25.177 44.766 25.321 ;
     RECT  45.576 24.935 46.314 25.321 ;
     RECT  43.956 25.321 46.314 25.475 ;
     RECT  50.688 25.435 50.706 25.475 ;
     RECT  43.956 25.475 44.514 25.547 ;
     RECT  42.912 25.213 42.93 25.555 ;
     RECT  42.372 25.555 43.218 25.613 ;
     RECT  42.912 25.613 43.218 25.709 ;
     RECT  43.956 25.547 44.478 25.709 ;
     RECT  16.416 24.205 16.866 25.717 ;
     RECT  43.956 25.709 44.262 25.745 ;
     RECT  47.34 25.241 48.33 26.011 ;
     RECT  47.16 26.011 48.33 26.051 ;
     RECT  47.844 26.051 48.33 26.131 ;
     RECT  49.32 25.241 49.338 26.131 ;
     RECT  50.184 25.867 50.202 26.131 ;
     RECT  45.576 25.475 46.314 26.257 ;
     RECT  0.072 24.539 5.31 26.293 ;
     RECT  18.615 2.413 18.897 26.293 ;
     RECT  47.844 26.131 50.202 26.293 ;
     RECT  0.072 26.293 5.526 26.329 ;
     RECT  16.416 25.717 17.406 26.329 ;
     RECT  18.288 26.293 18.897 26.329 ;
     RECT  47.844 26.293 50.706 26.357 ;
     RECT  45.576 26.257 46.386 26.401 ;
     RECT  0.072 26.329 5.598 26.429 ;
     RECT  50.184 26.357 50.706 26.429 ;
     RECT  47.844 26.357 49.338 26.519 ;
     RECT  45.504 26.401 46.854 26.555 ;
     RECT  0.072 26.429 5.526 26.627 ;
     RECT  43.956 25.745 43.974 26.671 ;
     RECT  43.956 26.671 44.118 26.789 ;
     RECT  50.688 26.429 50.706 26.789 ;
     RECT  0.072 26.627 0.126 26.825 ;
     RECT  0.864 26.627 5.526 26.825 ;
     RECT  47.844 26.519 49.23 26.825 ;
     RECT  44.748 26.797 44.766 26.833 ;
     RECT  45.504 26.555 46.602 26.833 ;
     RECT  16.416 26.329 18.897 27.067 ;
     RECT  44.748 26.833 46.602 27.095 ;
     RECT  42.912 25.709 42.93 27.139 ;
     RECT  44.892 27.095 46.602 27.167 ;
     RECT  6.804 26.941 6.822 27.175 ;
     RECT  6.768 27.175 6.822 27.176 ;
     RECT  42.516 27.139 42.93 27.307 ;
     RECT  6.768 27.176 6.786 27.329 ;
     RECT  42.372 27.307 42.93 27.337 ;
     RECT  42.372 27.337 43.182 27.365 ;
     RECT  22.068 27.175 22.086 27.481 ;
     RECT  21.348 27.481 22.482 27.571 ;
     RECT  23.22 27.481 23.238 27.571 ;
     RECT  24.015 2.413 24.297 27.571 ;
     RECT  50.652 27.163 50.67 27.595 ;
     RECT  42.768 27.365 43.182 27.635 ;
     RECT  21.348 27.571 24.297 27.707 ;
     RECT  42.768 27.635 42.93 27.707 ;
     RECT  47.016 27.355 47.034 27.715 ;
     RECT  47.844 26.825 49.194 27.715 ;
     RECT  22.86 27.707 24.297 27.743 ;
     RECT  47.016 27.715 49.194 27.743 ;
     RECT  47.16 27.743 49.194 27.751 ;
     RECT  23.184 27.743 24.297 27.779 ;
     RECT  23.184 27.779 23.202 27.869 ;
     RECT  42.768 27.707 42.786 27.869 ;
     RECT  47.16 27.751 49.374 27.869 ;
     RECT  50.652 27.595 50.706 27.869 ;
     RECT  0.108 26.825 0.126 27.877 ;
     RECT  0.864 26.825 5.238 27.877 ;
     RECT  21.348 27.707 22.086 27.905 ;
     RECT  47.16 27.869 47.178 27.905 ;
     RECT  48.276 27.869 49.374 27.905 ;
     RECT  50.688 27.869 50.706 28.139 ;
     RECT  49.104 27.905 49.338 28.211 ;
     RECT  9.108 27.841 9.126 28.409 ;
     RECT  0.108 27.877 5.238 29.165 ;
     RECT  0.864 29.165 5.238 29.363 ;
     RECT  0.108 29.165 0.126 29.371 ;
     RECT  0.036 29.371 0.126 29.795 ;
     RECT  0.864 29.363 1.422 30.145 ;
     RECT  2.304 29.363 5.238 30.145 ;
     RECT  0.864 30.145 5.238 30.569 ;
     RECT  0.036 29.795 0.054 30.649 ;
     RECT  4.932 30.569 5.238 30.749 ;
     RECT  0.864 30.569 4.05 31.621 ;
     RECT  15.84 27.067 18.897 31.621 ;
     RECT  0.864 31.621 4.158 31.721 ;
     RECT  34.815 2.413 35.097 33.304 ;
     RECT  35.892 33.241 35.91 33.304 ;
     RECT  34.815 33.304 35.91 33.341 ;
     RECT  35.892 33.341 35.91 33.539 ;
     RECT  0.036 30.649 0.126 33.583 ;
     RECT  0.864 31.721 3.978 33.583 ;
     RECT  0.036 33.583 3.978 34.781 ;
     RECT  0.864 34.781 3.978 35.213 ;
     RECT  0.864 35.213 3.762 36.077 ;
     RECT  30.852 36.751 30.87 36.797 ;
     RECT  30.528 36.811 30.546 36.851 ;
     RECT  1.98 36.077 3.762 37.319 ;
     RECT  1.98 37.319 3.33 37.373 ;
     RECT  0.036 34.781 0.054 37.435 ;
     RECT  0.864 36.077 1.206 37.435 ;
     RECT  0.036 37.435 1.206 37.805 ;
     RECT  21.348 27.905 21.366 37.859 ;
     RECT  15.84 31.621 19.242 37.975 ;
     RECT  1.188 37.805 1.206 38.237 ;
     RECT  2.016 37.373 3.33 38.669 ;
     RECT  0.036 37.805 0.054 38.923 ;
     RECT  0.036 38.923 0.126 38.957 ;
     RECT  0.108 38.957 0.126 39.101 ;
     RECT  2.052 38.669 3.33 39.533 ;
     RECT  25.956 40.459 25.974 40.531 ;
     RECT  26.784 40.459 26.802 40.531 ;
     RECT  2.304 39.533 3.33 40.559 ;
     RECT  25.956 40.531 26.802 40.559 ;
     RECT  26.244 40.559 26.802 40.589 ;
     RECT  2.304 40.559 3.222 40.631 ;
     RECT  4.932 30.749 5.166 40.703 ;
     RECT  4.932 40.703 4.95 40.829 ;
     RECT  2.304 40.631 3.114 41.261 ;
     RECT  2.415 41.261 3.114 42.025 ;
     RECT  2.304 42.025 3.114 42.125 ;
     RECT  2.415 42.125 3.114 42.179 ;
     RECT  0.108 41.143 0.126 42.295 ;
     RECT  0.108 42.295 0.162 42.557 ;
     RECT  0.144 42.557 0.162 42.989 ;
     RECT  15.84 37.975 19.674 47.179 ;
     RECT  14.796 47.155 14.814 47.191 ;
     RECT  15.804 47.179 19.674 47.191 ;
     RECT  2.415 42.179 3.006 47.309 ;
     RECT  14.796 47.191 19.674 47.425 ;
     RECT  2.415 47.309 2.862 47.453 ;
     RECT  14.796 47.425 19.746 47.551 ;
     RECT  14.76 47.551 19.746 47.731 ;
     RECT  14.472 47.731 19.746 47.849 ;
     RECT  14.472 47.849 19.674 47.921 ;
     RECT  13.215 2.413 13.497 48.271 ;
     RECT  14.472 47.921 19.494 48.271 ;
     RECT  13.215 48.271 19.494 48.461 ;
     RECT  22.788 48.469 22.806 48.541 ;
     RECT  14.4 48.461 19.494 48.667 ;
     RECT  22.752 48.541 22.806 48.703 ;
     RECT  28.152 48.667 28.17 48.703 ;
     RECT  14.4 48.667 20.178 48.739 ;
     RECT  26.424 48.541 26.442 48.739 ;
     RECT  27.9 48.703 28.17 48.739 ;
     RECT  14.4 48.739 20.43 48.775 ;
     RECT  21.744 48.541 21.762 48.775 ;
     RECT  22.716 48.703 22.806 48.775 ;
     RECT  24.015 27.779 24.297 48.811 ;
     RECT  26.352 48.739 26.442 48.811 ;
     RECT  27.9 48.739 28.242 48.811 ;
     RECT  27.9 48.811 28.458 48.901 ;
     RECT  29.415 2.413 29.697 48.901 ;
     RECT  26.352 48.811 26.802 48.937 ;
     RECT  27.9 48.901 29.697 48.937 ;
     RECT  21.672 48.775 22.806 48.973 ;
     RECT  23.688 48.811 24.297 48.973 ;
     RECT  21.528 48.973 22.806 49.045 ;
     RECT  21.348 49.045 22.806 49.081 ;
     RECT  34.815 33.341 35.097 49.081 ;
     RECT  30.78 49.081 30.798 49.171 ;
     RECT  23.616 48.973 24.297 49.207 ;
     RECT  30.708 49.171 30.798 49.207 ;
     RECT  33.156 48.775 33.174 49.207 ;
     RECT  37.62 48.973 37.638 49.207 ;
     RECT  25.488 49.207 25.506 49.243 ;
     RECT  26.28 48.937 26.802 49.243 ;
     RECT  34.704 49.081 35.097 49.243 ;
     RECT  21.348 49.081 22.842 49.271 ;
     RECT  33.012 49.207 33.174 49.279 ;
     RECT  37.476 49.207 37.638 49.279 ;
     RECT  30.708 49.207 30.942 49.291 ;
     RECT  34.704 49.243 35.154 49.315 ;
     RECT  30.6 49.291 30.942 49.342 ;
     RECT  23.616 49.207 24.354 49.351 ;
     RECT  32.94 49.279 33.174 49.351 ;
     RECT  37.368 49.279 37.638 49.351 ;
     RECT  14.4 48.775 20.538 49.379 ;
     RECT  2.415 47.453 2.697 49.427 ;
     RECT  7.815 2.413 8.097 49.427 ;
     RECT  13.215 48.461 13.497 49.427 ;
     RECT  27.792 48.937 29.697 49.427 ;
     RECT  40.215 2.413 40.497 49.427 ;
     RECT  45.615 27.167 45.897 49.427 ;
     RECT  23.616 49.351 24.534 49.441 ;
     RECT  14.508 49.379 20.538 49.469 ;
     RECT  23.256 49.441 24.534 49.469 ;
     RECT  25.488 49.243 26.802 49.469 ;
     RECT  34.668 49.315 35.334 49.469 ;
     RECT  37.08 49.351 37.746 49.469 ;
     RECT  25.488 49.469 26.658 49.477 ;
     RECT  14.508 49.469 19.314 49.505 ;
     RECT  14.508 49.505 14.526 49.517 ;
     RECT  15.3 49.505 19.314 49.517 ;
     RECT  23.256 49.469 24.39 49.517 ;
     RECT  25.308 49.477 26.658 49.517 ;
     RECT  20.052 49.469 20.538 49.531 ;
     RECT  21.348 49.271 22.122 49.531 ;
     RECT  27.792 49.427 29.505 49.531 ;
     RECT  30.564 49.342 30.942 49.531 ;
     RECT  32.76 49.351 33.174 49.531 ;
     RECT  37.08 49.469 37.638 49.531 ;
     RECT  18.144 49.517 19.314 49.541 ;
     RECT  23.436 49.517 24.39 49.541 ;
     RECT  20.052 49.531 22.122 49.565 ;
     RECT  27.612 49.531 29.505 49.565 ;
     RECT  36.9 49.531 37.638 49.565 ;
     RECT  15.372 49.517 16.686 49.577 ;
     RECT  18.576 49.541 19.314 49.577 ;
     RECT  20.052 49.565 20.07 49.577 ;
     RECT  21.06 49.565 22.122 49.577 ;
     RECT  23.724 49.541 24.39 49.577 ;
     RECT  27.612 49.565 27.63 49.577 ;
     RECT  30.42 49.531 30.978 49.577 ;
     RECT  32.58 49.531 33.246 49.577 ;
     RECT  36.9 49.565 36.918 49.577 ;
     RECT  25.56 49.517 26.658 49.649 ;
     RECT  2.415 49.427 2.505 49.697 ;
     RECT  7.815 49.427 7.905 49.697 ;
     RECT  13.215 49.427 13.305 49.697 ;
     RECT  18.615 49.577 19.314 49.697 ;
     RECT  28.44 49.565 29.505 49.697 ;
     RECT  40.215 49.427 40.305 49.697 ;
     RECT  45.615 49.427 45.705 49.697 ;
     RECT  34.74 49.469 35.334 49.853 ;
     RECT  22.068 49.577 22.122 50.669 ;
     RECT  19.296 49.697 19.314 50.765 ;
     RECT  22.104 50.669 22.122 50.765 ;
     RECT  23.832 49.577 24.39 50.765 ;
     RECT  25.56 49.649 25.578 50.765 ;
     RECT  26.64 49.649 26.658 50.765 ;
     RECT  28.44 49.697 28.998 50.765 ;
     RECT  35.316 49.853 35.334 50.765 ;
     RECT  30.708 49.577 30.726 51.725 ;
    LAYER M4 ;
     RECT  0.025 9.6 0.06 9.624 ;
     RECT  0.025 38.928 0.06 38.952 ;
     RECT  0.06 8.832 0.137 42.984 ;
     RECT  0.137 9.264 0.173 31.752 ;
     RECT  0.137 33.024 0.173 42.984 ;
     RECT  0.173 9.696 0.209 27.864 ;
     RECT  0.173 33.024 0.569 33.912 ;
     RECT  0.173 35.184 0.965 42.12 ;
     RECT  0.209 24.816 1.181 27.864 ;
     RECT  0.965 37.344 1.217 42.12 ;
     RECT  0.209 9.696 1.433 23.544 ;
     RECT  0.965 35.184 1.433 36.072 ;
     RECT  1.433 9.696 2.408 11.976 ;
     RECT  1.433 13.584 2.408 23.544 ;
     RECT  1.181 24.816 2.408 26.136 ;
     RECT  1.181 27.408 2.408 27.864 ;
     RECT  0.173 29.568 2.408 31.752 ;
     RECT  0.569 33.024 2.408 33.048 ;
     RECT  1.433 35.184 2.408 35.208 ;
     RECT  1.217 37.344 2.408 37.368 ;
     RECT  1.217 38.64 2.408 42.12 ;
     RECT  2.408 2.148 2.512 49.692 ;
     RECT  2.512 2.418 2.704 49.422 ;
     RECT  2.704 16.608 2.765 16.632 ;
     RECT  2.704 30.336 2.801 31.752 ;
     RECT  2.801 30.336 2.819 31.704 ;
     RECT  2.819 30.336 2.837 30.36 ;
     RECT  2.704 29.328 2.909 29.352 ;
     RECT  2.704 20.688 3.017 20.712 ;
     RECT  2.704 10.128 3.125 10.152 ;
     RECT  2.704 19.632 3.305 19.656 ;
     RECT  2.704 21.888 3.341 22.92 ;
     RECT  3.341 21.888 3.377 22.824 ;
     RECT  3.377 21.888 3.413 22.776 ;
     RECT  3.413 22.272 3.436 22.776 ;
     RECT  3.436 22.752 3.485 22.776 ;
     RECT  2.819 31.68 3.593 31.704 ;
     RECT  2.704 27.216 3.697 27.336 ;
     RECT  3.697 26.736 3.769 27.336 ;
     RECT  3.769 26.256 3.845 27.336 ;
     RECT  2.704 11.952 3.953 11.976 ;
     RECT  3.845 27.312 3.953 27.336 ;
     RECT  2.704 35.184 3.989 35.208 ;
     RECT  3.845 26.256 4.025 26.328 ;
     RECT  2.704 18.288 4.097 18.312 ;
     RECT  4.025 26.256 4.889 26.28 ;
     RECT  7.808 2.148 7.912 49.692 ;
     RECT  7.912 2.418 8.104 49.422 ;
     RECT  13.208 2.148 13.312 49.692 ;
     RECT  13.312 2.418 13.504 49.422 ;
     RECT  13.504 47.76 14.573 48.456 ;
     RECT  14.437 49.488 14.869 49.512 ;
     RECT  14.573 47.76 15.793 47.784 ;
     RECT  14.869 49.488 15.833 49.56 ;
     RECT  15.793 47.184 15.905 47.784 ;
     RECT  15.905 47.424 15.941 47.784 ;
     RECT  15.833 49.536 16.643 49.56 ;
     RECT  15.941 47.424 16.981 47.448 ;
     RECT  15.973 48.432 16.981 48.456 ;
     RECT  16.981 47.424 17.021 48.456 ;
     RECT  17.021 47.424 17.489 47.88 ;
     RECT  17.029 49.488 17.881 49.512 ;
     RECT  17.489 47.856 18.601 47.88 ;
     RECT  17.881 48.96 18.601 49.512 ;
     RECT  13.504 36.816 18.608 36.84 ;
     RECT  18.601 47.856 18.608 49.512 ;
     RECT  18.608 2.148 18.712 49.692 ;
     RECT  18.712 2.418 18.904 49.422 ;
     RECT  19.285 50.736 19.667 50.76 ;
     RECT  18.904 47.856 19.901 49.272 ;
     RECT  20.012 49.536 21.349 49.56 ;
     RECT  21.349 49.488 21.449 49.56 ;
     RECT  21.449 49.536 21.827 49.56 ;
     RECT  19.901 47.856 21.923 47.88 ;
     RECT  21.877 27.792 21.964 27.816 ;
     RECT  22.057 50.64 22.093 50.664 ;
     RECT  22.093 50.64 22.259 50.76 ;
     RECT  22.259 50.64 22.691 50.664 ;
     RECT  23.077 49.488 23.509 49.512 ;
     RECT  18.904 36.816 24.008 36.84 ;
     RECT  21.877 40.56 24.008 40.584 ;
     RECT  23.509 49.008 24.008 49.512 ;
     RECT  24.008 2.148 24.112 49.692 ;
     RECT  24.112 2.418 24.304 49.56 ;
     RECT  24.304 49.488 24.419 49.56 ;
     RECT  24.419 49.488 25.337 49.512 ;
     RECT  24.304 40.56 25.945 40.584 ;
     RECT  25.945 40.464 26.813 40.584 ;
     RECT  23.821 50.736 27.011 50.76 ;
     RECT  26.06 49.536 28.307 49.56 ;
     RECT  28.429 50.736 29.171 50.76 ;
     RECT  24.304 36.816 29.408 36.84 ;
     RECT  26.813 40.56 29.408 40.584 ;
     RECT  29.408 2.148 29.512 49.692 ;
     RECT  29.512 2.418 29.704 49.56 ;
     RECT  29.704 36.816 30.557 36.84 ;
     RECT  29.704 49.296 30.809 49.56 ;
     RECT  30.812 36.768 30.899 36.792 ;
     RECT  29.704 40.56 30.899 40.584 ;
     RECT  30.697 51.696 30.899 51.72 ;
     RECT  30.809 49.536 31.331 49.56 ;
     RECT  32.54 49.536 33.491 49.56 ;
     RECT  34.7 49.824 34.787 49.848 ;
     RECT  30.853 33.312 34.808 33.336 ;
     RECT  34.808 2.148 34.912 49.692 ;
     RECT  34.912 2.418 35.104 49.56 ;
     RECT  35.104 33.264 35.201 33.336 ;
     RECT  35.104 49.536 35.219 49.56 ;
     RECT  35.305 50.736 35.651 50.76 ;
     RECT  36.86 49.536 37.811 49.56 ;
     RECT  35.201 33.264 40.208 33.288 ;
     RECT  40.208 2.148 40.312 49.692 ;
     RECT  40.312 2.418 40.504 49.422 ;
     RECT  42.332 27.312 42.419 27.336 ;
     RECT  40.504 33.264 42.419 33.288 ;
     RECT  42.312 25.584 43.945 25.608 ;
     RECT  43.945 25.104 43.985 25.608 ;
     RECT  43.985 25.104 44.453 25.128 ;
     RECT  45.565 26.256 45.608 26.28 ;
     RECT  45.608 2.148 45.712 49.692 ;
     RECT  45.712 2.418 45.904 49.422 ;
     RECT  45.904 26.256 47.125 26.28 ;
     RECT  47.125 26.016 47.171 26.28 ;
     RECT  47.005 27.36 47.171 27.384 ;
     RECT  47.105 24.48 47.189 24.504 ;
     RECT  47.171 26.016 47.212 26.04 ;
     RECT  50.173 25.008 50.677 25.896 ;
     RECT  50.641 27.168 50.677 27.192 ;
     RECT  50.677 24.576 50.713 27.624 ;
     RECT  50.713 24.144 51.804 27.624 ;
    LAYER M5 ;
     RECT  2.4 2.137 2.52 2.151 ;
     RECT  7.8 2.137 7.92 2.151 ;
     RECT  13.2 2.137 13.32 2.151 ;
     RECT  18.6 2.137 18.72 2.151 ;
     RECT  24 2.137 24.12 2.151 ;
     RECT  29.4 2.137 29.52 2.151 ;
     RECT  34.8 2.137 34.92 2.151 ;
     RECT  40.2 2.137 40.32 2.151 ;
     RECT  45.6 2.137 45.72 2.151 ;
     RECT  2.4 2.151 2.712 21.877 ;
     RECT  2.4 21.877 3.384 22.307 ;
     RECT  47.136 24.469 47.16 27.395 ;
     RECT  2.4 22.307 2.712 30.325 ;
     RECT  2.4 30.325 2.808 30.755 ;
     RECT  42.384 25.573 42.408 33.299 ;
     RECT  13.2 2.151 13.512 36.805 ;
     RECT  30.864 33.301 30.888 40.595 ;
     RECT  13.2 36.805 14.04 47.749 ;
     RECT  21.888 27.781 21.912 47.891 ;
     RECT  13.2 47.749 14.472 48.467 ;
     RECT  18.6 2.151 18.912 48.997 ;
     RECT  24 2.151 24.312 48.997 ;
     RECT  13.2 48.467 14.04 49.477 ;
     RECT  17.904 48.997 18.912 49.477 ;
     RECT  23.52 48.997 24.312 49.477 ;
     RECT  13.2 49.477 15.768 49.525 ;
     RECT  17.04 49.477 18.912 49.525 ;
     RECT  21.36 49.477 21.384 49.525 ;
     RECT  23.088 49.477 25.272 49.525 ;
     RECT  29.4 2.151 29.712 49.525 ;
     RECT  34.8 2.151 35.112 49.525 ;
     RECT  2.4 30.755 2.712 49.689 ;
     RECT  7.8 2.151 8.112 49.689 ;
     RECT  13.2 49.525 18.912 49.689 ;
     RECT  40.2 2.151 40.512 49.689 ;
     RECT  45.6 2.151 45.912 49.689 ;
     RECT  2.4 49.689 2.52 49.703 ;
     RECT  7.8 49.689 7.92 49.703 ;
     RECT  13.2 49.689 18.72 49.703 ;
     RECT  29.4 49.525 31.32 49.703 ;
     RECT  40.2 49.689 40.32 49.703 ;
     RECT  45.6 49.689 45.72 49.703 ;
     RECT  34.8 49.525 35.208 49.813 ;
     RECT  20.064 49.525 21.816 50.629 ;
     RECT  23.088 49.525 28.296 50.629 ;
     RECT  20.064 50.629 28.296 50.725 ;
     RECT  34.752 49.813 35.208 50.725 ;
     RECT  14.016 49.703 18.36 51.792 ;
     RECT  19.632 50.725 29.16 51.792 ;
     RECT  30.432 49.703 31.32 51.792 ;
     RECT  32.592 49.525 33.48 51.792 ;
     RECT  34.752 50.725 35.64 51.792 ;
     RECT  36.912 49.525 37.8 51.792 ;
     RECT  45.912 24.469 47.136 27.395 ;
     RECT  29.712 33.301 30.864 40.595 ;
     RECT  14.04 48.467 14.472 49.477 ;
     RECT  15.768 49.477 17.04 49.525 ;
     RECT  18.912 49.525 20.064 49.689 ;
     RECT  21.816 49.525 23.088 50.629 ;
     RECT  28.296 49.525 29.4 49.703 ;
     RECT  31.32 49.525 32.592 51.708 ;
     RECT  33.48 49.525 34.8 49.813 ;
     RECT  18.72 49.689 20.064 49.703 ;
     RECT  18.36 49.703 20.064 50.725 ;
     RECT  28.296 49.703 30.432 50.725 ;
     RECT  33.48 49.813 34.752 51.708 ;
     RECT  18.36 50.725 19.632 51.708 ;
     RECT  29.16 50.725 30.432 51.708 ;
     RECT  35.64 50.725 36.912 51.708 ;
     RECT  18.408 51.708 18.72 51.792 ;
     RECT  18.84 51.708 19.152 51.792 ;
     RECT  19.272 51.708 19.584 51.792 ;
     RECT  29.208 51.708 29.52 51.792 ;
     RECT  29.64 51.708 29.952 51.792 ;
     RECT  30.072 51.708 30.384 51.792 ;
     RECT  31.368 51.708 31.68 51.792 ;
     RECT  31.8 51.708 32.112 51.792 ;
     RECT  32.232 51.708 32.544 51.792 ;
     RECT  33.528 51.708 33.84 51.792 ;
     RECT  33.96 51.708 34.272 51.792 ;
     RECT  34.392 51.708 34.704 51.792 ;
     RECT  35.688 51.708 36 51.792 ;
     RECT  36.12 51.708 36.432 51.792 ;
     RECT  36.552 51.708 36.864 51.792 ;
  END
END dsfd_vm_static_read_v1
END LIBRARY
